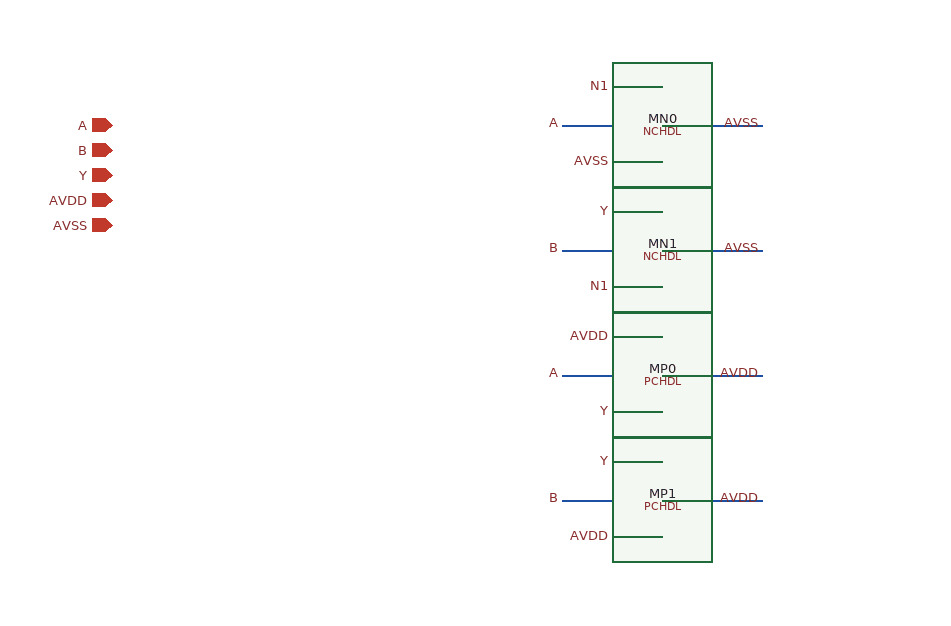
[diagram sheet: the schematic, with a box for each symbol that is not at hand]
v {xschem version=3.0.0 file_version=1.2 }
C {devices/iopin.sym} 0 0 0 0{name=p0 lab=A}
C {devices/iopin.sym} 0 20 0 0{name=p1 lab=B}
C {devices/iopin.sym} 0 40 0 0{name=p2 lab=Y}
C {devices/iopin.sym} 0 60 0 0{name=p3 lab=AVDD}
C {devices/iopin.sym} 0 80 0 0{name=p4 lab=AVSS}
C {SUN_TR_SK130NM/NCHDL.sym} 400 0 0 0 {name=MN0}
N 400.0 -30.0 440.0 -30.0{lab=N1}
C {devices/lab_pin.sym} 400.0 -30.0 0 0  {name=l0 sig_type=std_logic lab=N1 }
N 360.0 0.0 400.0 0.0{lab=A}
C {devices/lab_pin.sym} 360.0 0.0 0 0  {name=l1 sig_type=std_logic lab=A }
N 400.0 30.0 440.0 30.0{lab=AVSS}
C {devices/lab_pin.sym} 400.0 30.0 0 0  {name=l2 sig_type=std_logic lab=AVSS }
N 520.0 0.0 440.0 0.0{lab=AVSS}
C {devices/lab_pin.sym} 520.0 0.0 0 0  {name=l3 sig_type=std_logic lab=AVSS }
C {SUN_TR_SK130NM/NCHDL.sym} 400 100 0 0 {name=MN1}
N 400.0 70.0 440.0 70.0{lab=Y}
C {devices/lab_pin.sym} 400.0 70.0 0 0  {name=l4 sig_type=std_logic lab=Y }
N 360.0 100.0 400.0 100.0{lab=B}
C {devices/lab_pin.sym} 360.0 100.0 0 0  {name=l5 sig_type=std_logic lab=B }
N 400.0 130.0 440.0 130.0{lab=N1}
C {devices/lab_pin.sym} 400.0 130.0 0 0  {name=l6 sig_type=std_logic lab=N1 }
N 520.0 100.0 440.0 100.0{lab=AVSS}
C {devices/lab_pin.sym} 520.0 100.0 0 0  {name=l7 sig_type=std_logic lab=AVSS }
C {SUN_TR_SK130NM/PCHDL.sym} 400 200 0 0 {name=MP0}
N 400.0 230.0 440.0 230.0{lab=Y}
C {devices/lab_pin.sym} 400.0 230.0 0 0  {name=l8 sig_type=std_logic lab=Y }
N 360.0 200.0 400.0 200.0{lab=A}
C {devices/lab_pin.sym} 360.0 200.0 0 0  {name=l9 sig_type=std_logic lab=A }
N 400.0 170.0 440.0 170.0{lab=AVDD}
C {devices/lab_pin.sym} 400.0 170.0 0 0  {name=l10 sig_type=std_logic lab=AVDD }
N 520.0 200.0 440.0 200.0{lab=AVDD}
C {devices/lab_pin.sym} 520.0 200.0 0 0  {name=l11 sig_type=std_logic lab=AVDD }
C {SUN_TR_SK130NM/PCHDL.sym} 400 300 0 0 {name=MP1}
N 400.0 330.0 440.0 330.0{lab=AVDD}
C {devices/lab_pin.sym} 400.0 330.0 0 0  {name=l12 sig_type=std_logic lab=AVDD }
N 360.0 300.0 400.0 300.0{lab=B}
C {devices/lab_pin.sym} 360.0 300.0 0 0  {name=l13 sig_type=std_logic lab=B }
N 400.0 270.0 440.0 270.0{lab=Y}
C {devices/lab_pin.sym} 400.0 270.0 0 0  {name=l14 sig_type=std_logic lab=Y }
N 520.0 300.0 440.0 300.0{lab=AVDD}
C {devices/lab_pin.sym} 520.0 300.0 0 0  {name=l15 sig_type=std_logic lab=AVDD }
